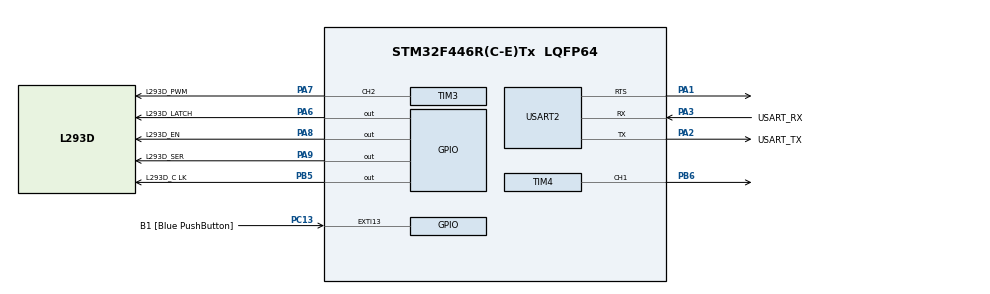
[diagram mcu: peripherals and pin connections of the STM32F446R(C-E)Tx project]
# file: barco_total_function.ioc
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Mcu.Family=STM32F4
Mcu.Name=STM32F446R(C-E)Tx
Mcu.Package=LQFP64
NVIC.PriorityGroup=NVIC_PRIORITYGROUP_0
PA1.Mode=RTS_Only
PA1.Signal=USART2_RTS
PA13.GPIO_Label=TMS
PA13.Mode=Serial_Wire
PA13.Signal=SYS_JTMS-SWDIO
PA14.GPIO_Label=TCK
PA14.Mode=Serial_Wire
PA14.Signal=SYS_JTCK-SWCLK
PA2.GPIO_Label=USART_TX
PA2.Mode=Asynchronous
PA2.Signal=USART2_TX
PA3.GPIO_Label=USART_RX
PA3.Mode=Asynchronous
PA3.Signal=USART2_RX
PA6.GPIO_Label=L293D_LATCH
PA6.Signal=GPIO_Output
PA7.GPIO_Label=L293D_PWM
PA7.Signal=S_TIM3_CH2
PA8.GPIO_Label=L293D_EN
PA8.Signal=GPIO_Output
PA9.GPIO_Label=L293D_SER
PA9.Signal=GPIO_Output
PB3.GPIO_Label=SWO
PB3.Signal=SYS_JTDO-SWO
PB5.GPIO_Label=L293D_C LK
PB5.Signal=GPIO_Output
PB6.Signal=S_TIM4_CH1
PC13.GPIO_Label=B1 [Blue PushButton]
PC13.GPIO_ModeDefaultEXTI=GPIO_MODE_IT_FALLING
PC13.Signal=GPXTI13
PC14-OSC32_IN.Mode=LSE-External-Oscillator
PC14-OSC32_IN.Signal=RCC_OSC32_IN
PC15-OSC32_OUT.Mode=LSE-External-Oscillator
PC15-OSC32_OUT.Signal=RCC_OSC32_OUT
PH0-OSC_IN.Mode=HSE-External-Oscillator
PH0-OSC_IN.Signal=RCC_OSC_IN
PH1-OSC_OUT.Mode=HSE-External-Oscillator
PH1-OSC_OUT.Signal=RCC_OSC_OUT
ProjectManager.HeapSize=0x200
ProjectManager.StackSize=0x400
ProjectManager.TargetToolchain=STM32CubeIDE
RCC.48MHZClocksFreq_Value=84000000
RCC.AHBCLKDivider=RCC_SYSCLK_DIV2
RCC.AHBFreq_Value=8000000
RCC.APB1CLKDivider=RCC_HCLK_DIV16
RCC.APB1Freq_Value=500000
RCC.APB1TimFreq_Value=1000000
RCC.APB2Freq_Value=8000000
RCC.APB2TimFreq_Value=8000000
RCC.CortexFreq_Value=8000000
RCC.FLatency-AdvancedSettings=FLASH_LATENCY_0
RCC.HCLKFreq_Value=8000000
RCC.HSE_VALUE=8000000
RCC.HSI_VALUE=16000000
RCC.PLLN=336
RCC.PLLP=RCC_PLLP_DIV4
RCC.SYSCLKFreq_VALUE=16000000
RCC.USBFreq_Value=168000000
RCC.VCOOutputFreq_Value=336000000
SH.S_TIM3_CH2.0=TIM3_CH2,PWM Generation2 CH2
SH.S_TIM4_CH1.0=TIM4_CH1,PWM Generation1 CH1
TIM3.Channel-PWM\ Generation2\ CH2=TIM_CHANNEL_2
TIM3.OCMode_PWM-PWM\ Generation2\ CH2=TIM_OCMODE_PWM1
TIM3.Period=1000
TIM3.Prescaler=84
TIM3.Pulse-PWM\ Generation2\ CH2=84
TIM4.Channel-PWM\ Generation1\ CH1=TIM_CHANNEL_1
TIM4.OCMode_PWM-PWM\ Generation1\ CH1=TIM_OCMODE_PWM1
TIM4.Period=1250
TIM4.Prescaler=0
TIM4.Pulse-PWM\ Generation1\ CH1=94
USART2.VirtualMode=VM_ASYNC
VP_TIM3_VS_ClockSourceINT.Mode=Internal
VP_TIM4_VS_ClockSourceINT.Mode=Internal
board=NUCLEO-F446RE

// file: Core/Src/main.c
/* USER CODE BEGIN Header */
/**
  ******************************************************************************
  * @file           : main.c
  * @brief          : Main program body
  ******************************************************************************
  * @attention
  *
  * Copyright (c) 2024 STMicroelectronics.
  * All rights reserved.
  *
  * This software is licensed under terms that can be found in the LICENSE file
  * in the root directory of this software component.
  * If no LICENSE file comes with this software, it is provided AS-IS.
  *
  ******************************************************************************
  */
/* USER CODE END Header */
#include "main.h"

/* USER CODE BEGIN Includes */
#include "pwm.h"
#include "MOTOReLEME.h"
/* USER CODE END Includes */

TIM_HandleTypeDef htim4;
TIM_HandleTypeDef htim3;
UART_HandleTypeDef huart2;

void SystemClock_Config(void);
static void MX_GPIO_Init(void);
static void MX_USART2_UART_Init(void);
static void MX_TIM4_Init(void);
static void MX_TIM3_Init(void);

int main(void)
{

  /* MCU Configuration--------------------------------------------------------*/

  /* Reset of all peripherals, Initializes the Flash interface and the Systick. */
  HAL_Init();

  /* Configure the system clock */
  SystemClock_Config();

  /* Initialize all configured peripherals */
  MX_GPIO_Init();
  MX_USART2_UART_Init();
  MX_TIM4_Init();
  MX_TIM3_Init();
  /* USER CODE BEGIN 2 */
  //Rudder_Control(htim4, 100,10);
  /* USER CODE END 2 */

  /* Infinite loop */
  while (1)
  {

    /* USER CODE BEGIN 3 */
	  //HAL_Delay(2000);
	  Rudder_Control(htim4, TIM_CHANNEL_1, 44,10);
	  HAL_Delay(2000);
	  Rudder_Control(htim4, TIM_CHANNEL_1, 144,10);

	  Motor_Control(htim3, TIM_CHANNEL_2, true, true, 500); // Enable motor, forward direction, 50% speed
	  HAL_Delay(2000); // Wait for 2 seconds
	  Motor_Control(htim3, TIM_CHANNEL_2, false, true, 0); // Disable motor

  }
  /* USER CODE END 3 */
}

void SystemClock_Config(void)
{
  RCC_OscInitTypeDef RCC_OscInitStruct = {0};
  RCC_ClkInitTypeDef RCC_ClkInitStruct = {0};

  /** Configure the main internal regulator output voltage
  */
  __HAL_RCC_PWR_CLK_ENABLE();
  __HAL_PWR_VOLTAGESCALING_CONFIG(PWR_REGULATOR_VOLTAGE_SCALE3);

  /** Initializes the RCC Oscillators according to the specified parameters
  * in the RCC_OscInitTypeDef structure.
  */
  RCC_OscInitStruct.OscillatorType = RCC_OSCILLATORTYPE_HSI;
  RCC_OscInitStruct.HSIState = RCC_HSI_ON;
  RCC_OscInitStruct.HSICalibrationValue = RCC_HSICALIBRATION_DEFAULT;
  RCC_OscInitStruct.PLL.PLLState = RCC_PLL_NONE;
  if (HAL_RCC_OscConfig(&RCC_OscInitStruct) != HAL_OK)
  {
    Error_Handler();
  }

  /** Initializes the CPU, AHB and APB buses clocks
  */
  RCC_ClkInitStruct.ClockType = RCC_CLOCKTYPE_HCLK|RCC_CLOCKTYPE_SYSCLK
                              |RCC_CLOCKTYPE_PCLK1|RCC_CLOCKTYPE_PCLK2;
  RCC_ClkInitStruct.SYSCLKSource = RCC_SYSCLKSOURCE_HSI;
  RCC_ClkInitStruct.AHBCLKDivider = RCC_SYSCLK_DIV64;
  RCC_ClkInitStruct.APB1CLKDivider = RCC_HCLK_DIV8;
  RCC_ClkInitStruct.APB2CLKDivider = RCC_HCLK_DIV8;

  if (HAL_RCC_ClockConfig(&RCC_ClkInitStruct, FLASH_LATENCY_0) != HAL_OK)
  {
    Error_Handler();
  }
}

/**
  * @param None
  * @retval None
  */

static void MX_TIM4_Init(void)
{

  TIM_ClockConfigTypeDef sClockSourceConfig = {0};
  TIM_MasterConfigTypeDef sMasterConfig = {0};
  TIM_OC_InitTypeDef sConfigOC = {0};

  htim4.Instance = TIM4;
  htim4.Init.Prescaler = 0;
  htim4.Init.CounterMode = TIM_COUNTERMODE_UP;
  htim4.Init.Period = 1250;
  htim4.Init.ClockDivision = TIM_CLOCKDIVISION_DIV1;
  htim4.Init.AutoReloadPreload = TIM_AUTORELOAD_PRELOAD_DISABLE;
  if (HAL_TIM_Base_Init(&htim4) != HAL_OK)
  {
    Error_Handler();
  }
  sClockSourceConfig.ClockSource = TIM_CLOCKSOURCE_INTERNAL;
  if (HAL_TIM_ConfigClockSource(&htim4, &sClockSourceConfig) != HAL_OK)
  {
    Error_Handler();
  }
  if (HAL_TIM_PWM_Init(&htim4) != HAL_OK)
  {
    Error_Handler();
  }
  sMasterConfig.MasterOutputTrigger = TIM_TRGO_RESET;
  sMasterConfig.MasterSlaveMode = TIM_MASTERSLAVEMODE_DISABLE;
  if (HAL_TIMEx_MasterConfigSynchronization(&htim4, &sMasterConfig) != HAL_OK)
  {
    Error_Handler();
  }
  sConfigOC.OCMode = TIM_OCMODE_PWM1;
  sConfigOC.Pulse = 94;
  sConfigOC.OCPolarity = TIM_OCPOLARITY_HIGH;
  sConfigOC.OCFastMode = TIM_OCFAST_DISABLE;
  if (HAL_TIM_PWM_ConfigChannel(&htim4, &sConfigOC, TIM_CHANNEL_1) != HAL_OK)
  {
    Error_Handler();
  }
  HAL_TIM_MspPostInit(&htim4);

}

static void MX_TIM3_Init(void)
{

  TIM_ClockConfigTypeDef sClockSourceConfig = {0};
  TIM_MasterConfigTypeDef sMasterConfig = {0};
  TIM_OC_InitTypeDef sConfigOC = {0};

  htim3.Instance = TIM3;
  htim3.Init.Prescaler = 10;
  htim3.Init.CounterMode = TIM_COUNTERMODE_UP;
  htim3.Init.Period = 1000;
  htim3.Init.ClockDivision = TIM_CLOCKDIVISION_DIV1;
  htim3.Init.AutoReloadPreload = TIM_AUTORELOAD_PRELOAD_DISABLE;
  if (HAL_TIM_Base_Init(&htim3) != HAL_OK)
  {
    Error_Handler();
  }
  sClockSourceConfig.ClockSource = TIM_CLOCKSOURCE_INTERNAL;
  if (HAL_TIM_ConfigClockSource(&htim3, &sClockSourceConfig) != HAL_OK)
  {
    Error_Handler();
  }
  if (HAL_TIM_PWM_Init(&htim3) != HAL_OK)
  {
    Error_Handler();
  }
  sMasterConfig.MasterOutputTrigger = TIM_TRGO_RESET;
  sMasterConfig.MasterSlaveMode = TIM_MASTERSLAVEMODE_DISABLE;
  if (HAL_TIMEx_MasterConfigSynchronization(&htim3, &sMasterConfig) != HAL_OK)
  {
    Error_Handler();
  }
  sConfigOC.OCMode = TIM_OCMODE_PWM1;
  sConfigOC.Pulse = 0;
  sConfigOC.OCPolarity = TIM_OCPOLARITY_HIGH;
  sConfigOC.OCFastMode = TIM_OCFAST_DISABLE;
  if (HAL_TIM_PWM_ConfigChannel(&htim3, &sConfigOC, TIM_CHANNEL_2) != HAL_OK)
  {
    Error_Handler();
  }
  HAL_TIM_MspPostInit(&htim3);

}

static void MX_USART2_UART_Init(void)
{

  huart2.Instance = USART2;
  huart2.Init.BaudRate = 115200;
  huart2.Init.WordLength = UART_WORDLENGTH_8B;
  huart2.Init.StopBits = UART_STOPBITS_1;
  huart2.Init.Parity = UART_PARITY_NONE;
  huart2.Init.Mode = UART_MODE_TX_RX;
  huart2.Init.HwFlowCtl = UART_HWCONTROL_NONE;
  huart2.Init.OverSampling = UART_OVERSAMPLING_16;
  if (HAL_UART_Init(&huart2) != HAL_OK)
  {
    Error_Handler();
  }

}

static void MX_GPIO_Init(void)
{
  GPIO_InitTypeDef GPIO_InitStruct = {0};

  /* GPIO Ports Clock Enable */
  __HAL_RCC_GPIOC_CLK_ENABLE();
  __HAL_RCC_GPIOH_CLK_ENABLE();
  __HAL_RCC_GPIOA_CLK_ENABLE();
  __HAL_RCC_GPIOB_CLK_ENABLE();

  /*Configure GPIO pin Output Level */
  HAL_GPIO_WritePin(GPIOA, L293D_LATCH_Pin|L293D_EN_Pin|L293D_SER_Pin, GPIO_PIN_RESET);

  /*Configure GPIO pin Output Level */
  HAL_GPIO_WritePin(L293D_C_LK_GPIO_Port, L293D_C_LK_Pin, GPIO_PIN_RESET);

  /*Configure GPIO pin : B1_Pin */
  GPIO_InitStruct.Pin = B1_Pin;
  GPIO_InitStruct.Mode = GPIO_MODE_IT_FALLING;
  GPIO_InitStruct.Pull = GPIO_NOPULL;
  HAL_GPIO_Init(B1_GPIO_Port, &GPIO_InitStruct);

  /*Configure GPIO pins : L293D_LATCH_Pin L293D_EN_Pin L293D_SER_Pin */
  GPIO_InitStruct.Pin = L293D_LATCH_Pin|L293D_EN_Pin|L293D_SER_Pin;
  GPIO_InitStruct.Mode = GPIO_MODE_OUTPUT_PP;
  GPIO_InitStruct.Pull = GPIO_NOPULL;
  GPIO_InitStruct.Speed = GPIO_SPEED_FREQ_LOW;
  HAL_GPIO_Init(GPIOA, &GPIO_InitStruct);

  /*Configure GPIO pin : L293D_C_LK_Pin */
  GPIO_InitStruct.Pin = L293D_C_LK_Pin;
  GPIO_InitStruct.Mode = GPIO_MODE_OUTPUT_PP;
  GPIO_InitStruct.Pull = GPIO_NOPULL;
  GPIO_InitStruct.Speed = GPIO_SPEED_FREQ_LOW;
  HAL_GPIO_Init(L293D_C_LK_GPIO_Port, &GPIO_InitStruct);

}

void Error_Handler(void)
{
  __disable_irq();
  while (1)
  {
  }
}
